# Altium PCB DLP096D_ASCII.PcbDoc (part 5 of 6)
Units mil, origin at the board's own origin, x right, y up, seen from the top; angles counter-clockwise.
Board outline 4950 x 3159.45 mil, 8 copper layers (Top Layer, GND1, SIGNAL1, POWER1, POWER2, SIGNAL2, GND2, Bottom Layer), stack 60.4 mil thick; 328 components, 223 nets, 1380 pads, 856 vias.

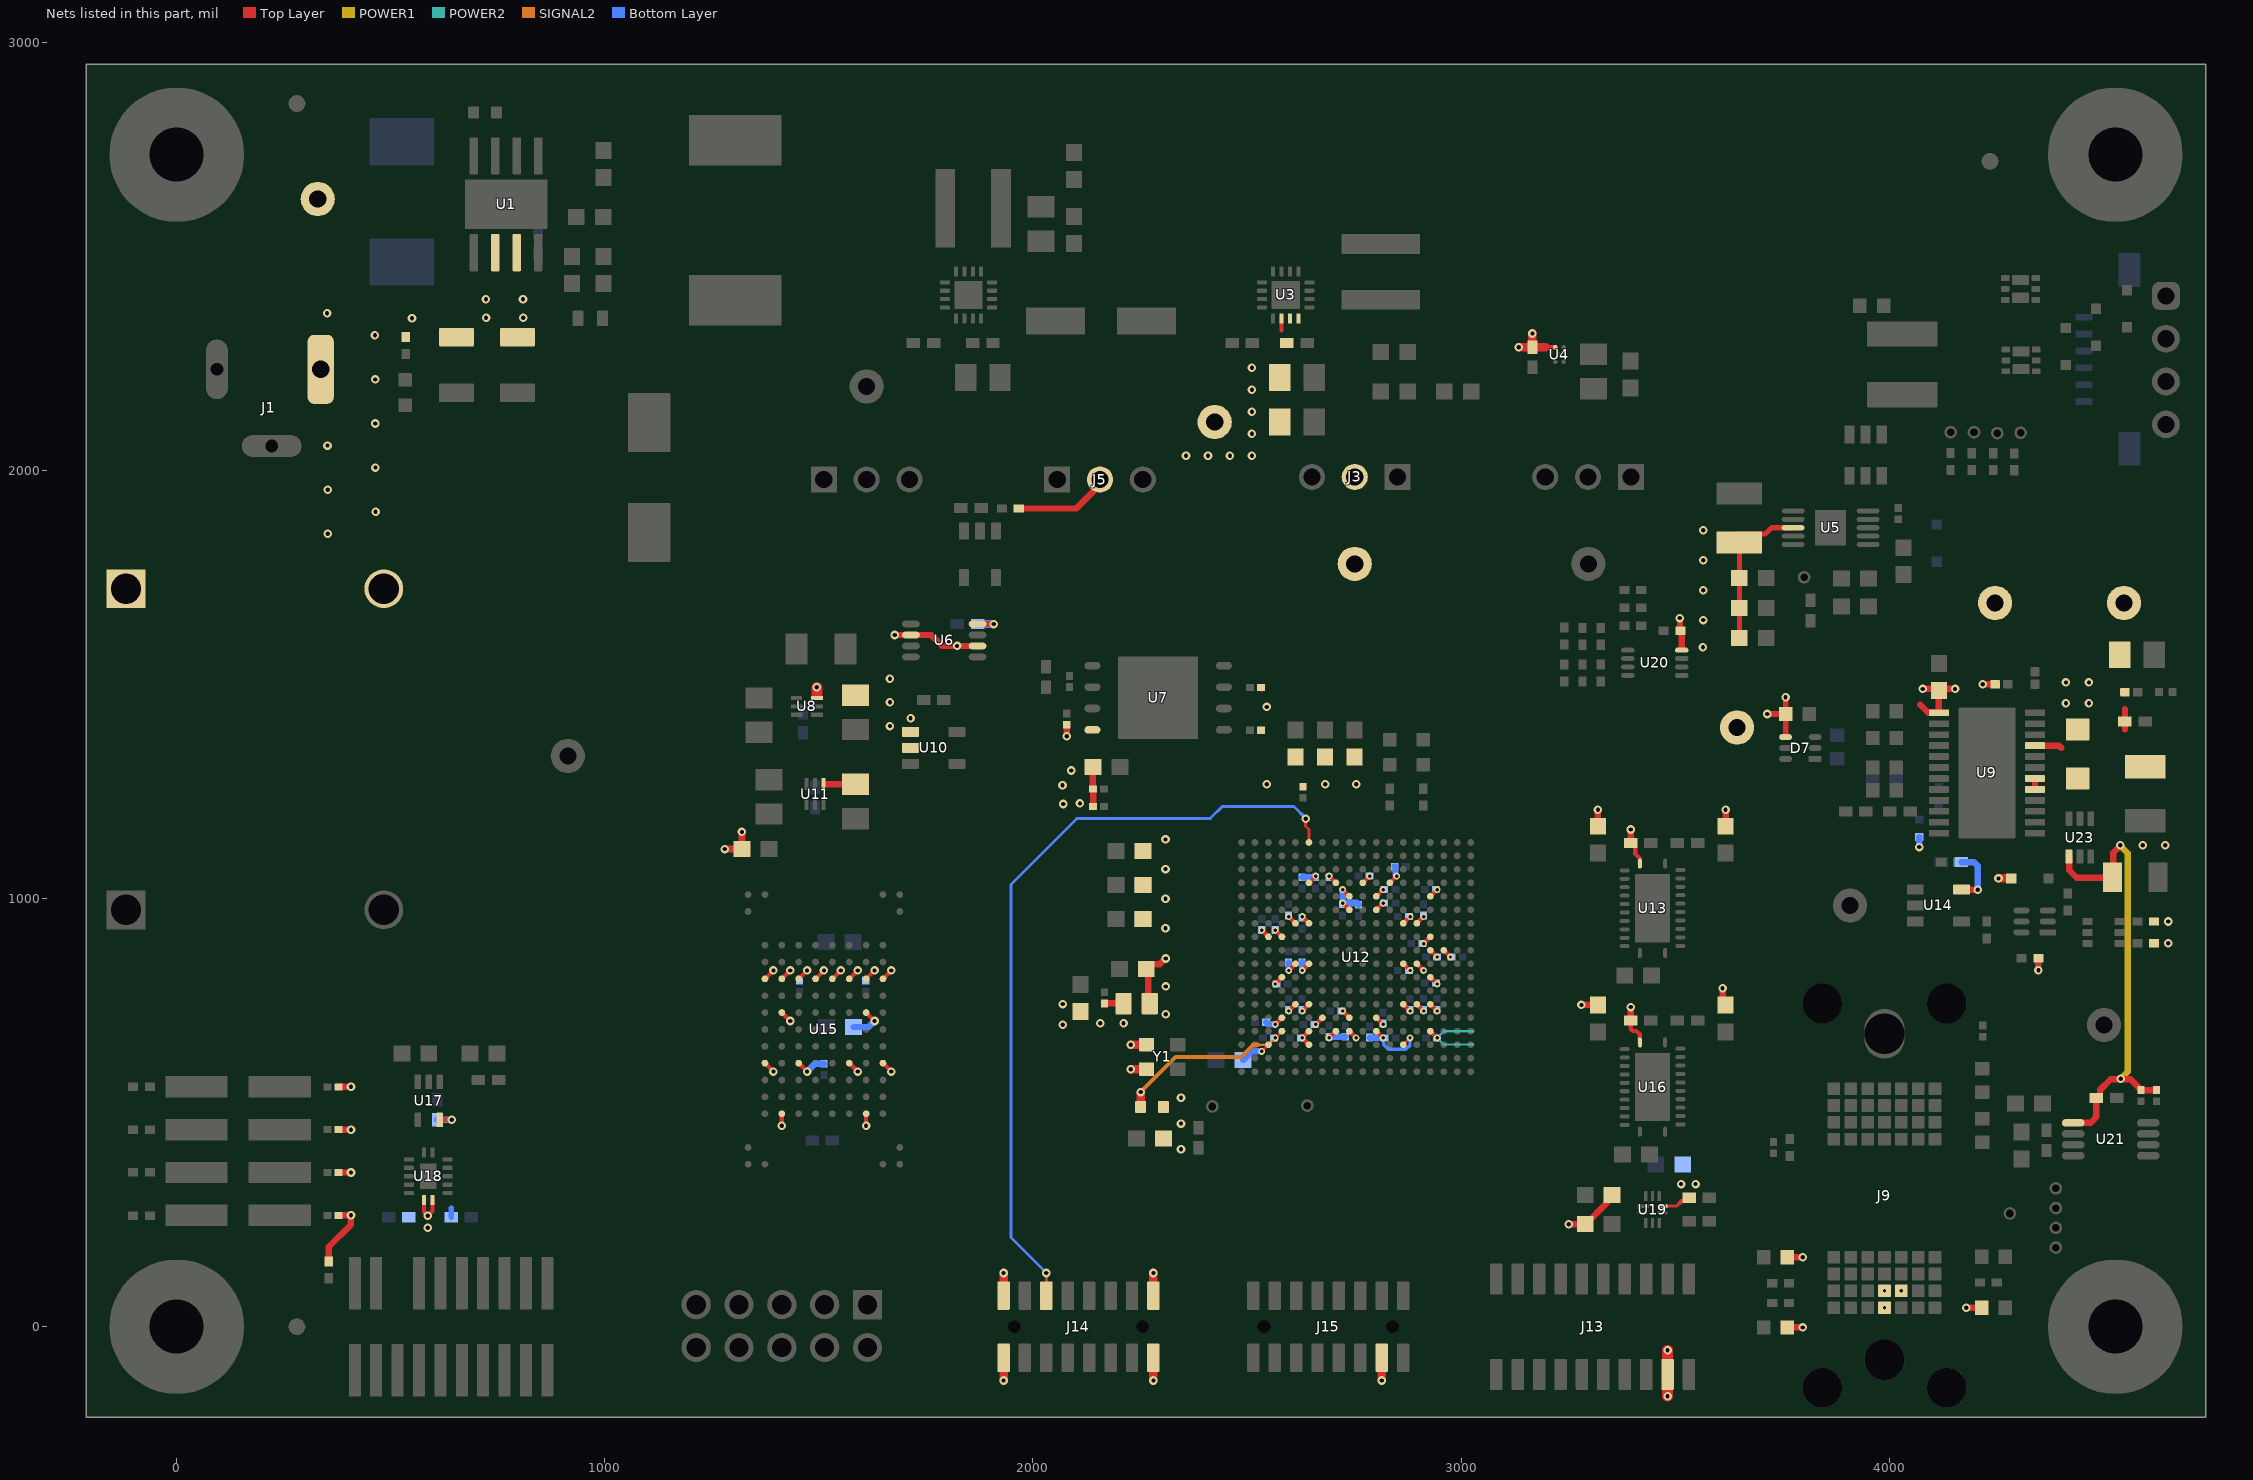
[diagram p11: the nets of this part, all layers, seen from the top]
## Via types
v1: diameter 20, hole 10, Top Layer to Bottom Layer, tented top, 596 vias
v2: diameter 16, hole 8, Top Layer to Bottom Layer, tented both sides, 126 vias
v3: diameter 16, hole 8.01, Top Layer to Bottom Layer, tented top, 63 vias
v4: diameter 19.68, hole 7.87, Top Layer to Bottom Layer, 37 vias
v5: diameter 16, hole 8.02, Top Layer to Bottom Layer, tented bottom, 22 vias
v6: diameter 24.8, hole 12.99, Top Layer to Bottom Layer, 6 vias
v7: diameter 19.68, hole 7.87, Top Layer to Bottom Layer, tented both sides, 6 vias

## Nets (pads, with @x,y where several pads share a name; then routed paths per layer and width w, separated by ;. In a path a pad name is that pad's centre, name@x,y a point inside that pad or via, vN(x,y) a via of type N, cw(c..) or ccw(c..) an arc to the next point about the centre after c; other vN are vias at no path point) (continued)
UART0_TXD: J14.12 U12.A6 | length 1831.9
  Top Layer w6.5: J14.12@2031.28,72.44 v1(2031.28,125.42) ; v1(2636.82,1186.35) 2636.82,1169.04 2644.56,1161.3 U12.A6@2644.56,1131.16
  Bottom Layer w6.5: v1(2031.28,125.42) 1948.36,208.34 1948.36,1033 2102.5,1187.14 2413.88,1187.14 2442,1215.25 2609.28,1215.25 2638.18,1186.35 v1(2636.82,1186.35)
VBIAS: C25.2 C64.1 J9.D15 R19.2 R42.2 TP8.1 U9.13 | length 275.3
  Top Layer w15: C64.1@3762.04,-1.74 v1(3797.78,-1.74) ; 4072.18,1452.7 4090.85,1434.04 U9.13@4115.92,1434.04 C25.2@4115.92,1489.65 ; v1(4078.14,1489.65) C25.2@4115.92,1489.65 ; v1(4153.71,1489.65) C25.2@4115.92,1489.65 ; v1(4218.45,1500.46) R19.2@4247.46,1500.46 ; v1(4348.41,832.48) R42.2@4348.41,860.32
  other v5: 3988.89,44.37
VDDA1V8_OSC_PLL_F: C553.1 FB2.2 U12.R4 | length 423.7
  Top Layer w6.5: v3(2565.82,674.47) U12.R4@2581.57,690.21
  Top Layer w20: FB2.2@2251.51,513.33 v1(2251.51,548.07)
  SIGNAL2 w5: 2525.52,658.67 2550.03,658.67 v3(2565.82,674.47)
  SIGNAL2 w10: v1(2251.51,548.07) 2333.18,629.75 2485.88,629.75 2514.8,658.67 2525.52,658.67
VDDA33_F: C46.1 C542.1 C543.1 C546.1 R74.2 U12.P7 U12.P9 U12.P11 | length 206.8
  Top Layer w10: v3(2660.31,705.96) U12.P7@2676.06,721.71 ; v3(2723.3,737.46) U12.P9@2739.05,721.71 ; U12.P11@2802.05,721.71 v3(2817.79,705.96)
  Top Layer w15: R74.2@2272.83,754.57 2268.76,758.63 2268.76,831.77 C46.1@2264.7,835.83 2275.9,847.03 2295.82,847.03 2308.73,859.94 v1(2310.09,859.94)
  other v1: 2310.09,729.65 2310.09,794.8
VDDA_LDO_1V8: C54.1 C547.1 C548.1 C549.1 C551.1 C552.1 FB2.1 U12.R6 U12.R8 U12.R11 U12.T6 U12.T13 | length 285.7
  Top Layer w6: U12.T13@2865.04,658.72 2865.04,658.89 2880.63,674.48 v3(2880.63,674.65)
  Top Layer w10: U12.T6@2644.56,658.72 v3(2628.82,674.47) U12.R6@2644.56,690.21 ; v3(2691.81,674.47) U12.R8@2707.56,690.21 ; U12.R11@2802.05,690.21 v3(2817.79,674.47)
  Bottom Layer w8: v3(2817.79,674.47) 2819.46,672.8 2819.46,658.05 2829.46,648.05 2871.08,648.05 2880.63,657.6 v3(2880.63,674.65)
  Bottom Layer w15: v3(2691.81,674.47) 2694.56,677.22 C547.1@2729.62,677.22 ; C549.1@2786.3,675.25 2817.01,675.25 v3(2817.79,674.47)
  other v1: 2345.8,414.17 2345.8,474.48 2345.8,534.79
VDDAR: C43.1 C44.1 C45.1 C509.1 C513.1 C515.1 C516.1 C517.1 C518.1 C519.1 C520.1 C521.1 C522.1 C523.1 C525.1 C528.1 C529.1 C530.1 C531.1 C532.1 C538.1 C539.1 C540.1 C541.1 J3.2 R36.2 TP6.1 U12.D10 U12.E9 U12.E11 U12.F9 U12.F11 U12.G5 U12.G6 U12.G13 U12.G14 U12.H3 U12.J15 U12.J16 U12.K5 U12.K6 U12.K13 U12.K14 U12.N5 U12.N6 U12.N13 U12.N14 U12.R9 | length 655.2
  Top Layer w10: v3(2534.33,926.43) U12.H3@2550.08,910.69 ; v3(2597.32,737.46) U12.N5@2613.07,753.21 ; v2(2597.32,831.95) U12.K5@2613.07,847.69 ; v3(2597.32,957.93) U12.G5@2613.07,942.18 ; v3(2628.82,737.46) U12.N6@2644.56,753.21 ; v2(2628.82,831.95) U12.K6@2644.56,847.69 ; v3(2628.82,957.93) U12.G6@2644.56,942.18 ; v3(2723.3,989.43) U12.F9@2739.05,973.68 ; v2(2723.3,1020.92) U12.E9@2739.05,1005.17 ; U12.R9@2739.05,690.21 v2(2754.8,674.47) ; U12.D10@2770.55,1036.67 v3(2786.3,1052.42) ; U12.F11@2802.05,973.68 v3(2817.79,989.43) ; U12.E11@2802.05,1005.17 v3(2817.79,1020.92) ; U12.N13@2865.04,753.21 v3(2880.79,737.46) ; U12.K13@2865.04,847.69 v3(2880.79,831.95) ; U12.G13@2865.04,942.18 v3(2880.79,957.93) ; U12.N14@2896.53,753.21 v3(2912.28,737.46) ; U12.K14@2896.53,847.69 v2(2912.28,831.95) ; U12.G14@2896.53,942.18 v3(2912.28,957.93) ; U12.J15@2928.03,879.19 v3(2943.78,863.44) ; U12.J16@2959.53,879.19 v3(2975.27,863.44)
  Top Layer w15.75: v1(1280.27,1115.55) R36.2@1320.27,1115.55 v1(1320.27,1155.55)
  Bottom Layer w15.75: C529.1@2597.27,850.28 2597.27,831.99 v2(2597.32,831.95) ; v2(2628.82,831.95) C528.1@2628.82,850.45 ; v2(2723.3,1020.92) v3(2723.3,989.43) 2756.47,989.43 2759.2,986.7 2759.99,986.7 2760.38,986.3 C520.1@2760.38,985.51
  other v1: 2309.5,930.36 2309.5,999.59 2309.5,1068.81 2309.5,1138.04
VDDS33: C9.1 C10.1 C13.1 C30.1 C31.1 C32.1 C35.1 C36.1 C38.1 C39.2 C41.1 C47.1 C48.1 C49.1 C56.1 C65.1 C71.1 C501.1 C507.1 C508.1 C510.1 C524.1 C527.1 C533.1 C534.1 C535.1 C544.1 C545.1 C550.1 C555.1 C556.1 C557.2 J5.2 J13.3 J14.1 J14.2 J14.15 J14.16 J15.3 R10.2 R23.2 R25.2 R26.2 R29.2 R34.1 R35.1 R44.1 R45.1 R47.2 R63.2 R67.2 R69.2 R70.2 R72.1 R74.1 R75.1 R77.2 R85.2 R86.2 R505.2 R532.1 TP5.1 U3.10 U3.11 U3.12 U4.A1 U6.8 U7.8 U12.D8 U12.D12 U12.H4 U12.H15 U12.L15 U12.P4 U12.R15 U13.1 U14.5 U15.F2 U15.F3 U15.F4 U15.F5 U15.F6 U15.F7 U15.F8 U15.F9 U15.H3 U15.H8 U15.L2 U15.L4 U15.L7 U15.L9 U15.P3 U15.P8 U16.1 U17.5 U18.1 U18.14 U19.7 U20.8 U21.1 U23.1 | length 4153.9
  Top Layer w7: U19.7@3470.73,281.42 3503.17,281.42 3509.54,287.79
  Top Layer w9.4: 2580.55,2326.58 U3.10@2580.55,2354.73
  Top Layer w9.8: U18.14@577.74,296.29 577.74,268.23 v1(586.67,259.31) 597.43,270.06 U18.1@597.43,296.29 ; U17.5@614.46,483.25 v1(642.38,483.25)
  Top Layer w10: U15.L2@1374.03,615.56 v1(1393.72,595.88) ; U15.F2@1374.03,812.41 v1(1393.72,832.1) ; v1(1413.4,469.61) U15.P3@1413.4,497.45 ; U15.H3@1413.4,733.67 v1(1433.09,713.99) ; U15.F3@1413.4,812.41 v1(1433.09,832.1) ; U15.L4@1452.77,615.56 v1(1472.46,595.88) ; U15.F4@1452.77,812.41 v1(1472.46,832.1) ; U15.F5@1492.14,812.41 v1(1511.83,832.1) ; U15.F6@1531.51,812.41 v1(1551.2,832.1) ; U15.L7@1570.88,615.56 v1(1590.57,595.88) ; U15.F7@1570.88,812.41 v1(1590.57,832.1) ; v1(1610.25,469.61) U15.P8@1610.25,497.45 ; U15.H8@1610.25,733.67 v1(1629.94,713.99) ; U15.F8@1610.25,812.41 v1(1629.94,832.1) ; U15.L9@1649.62,615.56 v1(1669.31,595.88) ; U15.F9@1649.62,812.41 v1(1669.31,832.1) ; v2(2565.82,705.96) U12.P4@2581.57,721.71 ; v3(2565.82,926.43) U12.H4@2581.57,910.69 ; v3(2691.81,1052.42) U12.D8@2707.56,1036.67 ; U12.D12@2833.54,1036.67 v3(2849.29,1052.42) ; v3(2912.28,894.94) U12.H15@2928.03,910.69 ; U12.R15@2928.03,690.21 v3(2943.78,674.47) ; U12.L15@2928.03,816.2 v3(2943.78,800.45) ; 3197.67,2287.86 U4.A1@3219.56,2287.86 ; C49.1@3396.24,714.84 3396.24,695.62 3400.96,690.9 3409.55,690.9 3417.54,682.9 U16.1@3417.54,664.13 ; C41.1@3396.24,1129.49 3400.13,1129.49 3406.94,1122.68 3406.94,1104.36 3417.54,1093.75 U13.1@3417.54,1081.62 ; 3509.54,287.79 3516.22,294.47 3525.48,294.47 C56.1@3532.29,301.28
  Top Layer w14.5: U6.8@1870.52,1641.21 v1(1908.39,1641.21) ; v1(2078.92,1378.88) R25.2@2078.92,1405.98
  Top Layer w15: R75.1@355.48,152.65 355.48,186.96 406.22,237.7 406.22,259.24 v1(407.18,260.2) R70.2@378.12,260.2 ; R67.2@378.12,360.2 v1(407.18,360.2) ; R63.2@378.12,460.2 v1(407.18,460.2) ; R47.2@378.12,560.2 v1(407.18,560.2) ; R77.2@1966.86,1911 2101.29,1911 2156.54,1966.24 J5.2@2156.54,1978.66 ; C35.1@2140.07,1256.14 C38.1@2140.07,1307.14 ; C36.1@2140.66,1216.46 C35.1@2140.66,1256.14 ; C48.1@2167.41,755.02 2211.29,755.02 R74.1@2211.74,754.57 ; R23.2@2532.81,1493.21 2533.6,1493.21 2534.37,1492.44 R23.2@2534.37,1491.65 ; R29.2@2631.07,1261.37 R29.2@2631.07,1262.16 ; C31.1@2682.04,1330.49 C31.1@2682.46,1330.07 ; C32.1@2751.51,1330.49 C32.1@2754.33,1327.67 ; v1(3251.14,239.44) R72.1@3289.83,239.44 3290.81,239.44 3340.63,289.26 3340.63,296.71 3351.84,307.91 R69.2@3352.82,307.91 ; v1(3280.94,751.51) R44.1@3319.63,751.51 ; R34.1@3319.63,1169 v1(3319.63,1207.69) ; C49.1@3396.24,714.84 v1(3396.24,746.65) ; C41.1@3396.24,1129.49 v1(3396.24,1161.3) ; v1(3510.51,1655.12) 3511.32,1654.32 3511.32,1626 C65.1@3512.12,1625.2 3513.07,1625.2 3515.42,1622.86 U20.8@3515.5,1583.57 ; v1(3610.77,790.2) 3610.77,758.51 R45.1@3617.77,751.51 ; R35.1@3617.77,1169 v1(3617.77,1207.69) ; U14.5@4170.76,1020.81 v1(4206.6,1020.81) ; U23.1@4419.7,1098.19 4420.07,1097.82 4420.07,1066.17 4437.83,1048.42 4520.04,1048.42 C39.2@4521.41,1049.8 4523.25,1051.64 4523.25,1106.75 4539.82,1123.31 v1(4539.82,1124.66) ; U21.1@4429.64,476.05 4430.16,476.57 4470.41,476.57 4483.88,490.04 C71.1@4483.92,533.99 ; C71.1@4483.92,533.99 4487.86,533.99 4492.17,538.31 4492.17,553 4517.29,578.13 4563.5,578.13 4588.16,553.47 R86.2@4588.16,552.68 R86.2@4588.16,552.68 4624.57,552.74 R85.2@4624.63,552.8
  Top Layer w20: v1(1931.28,-125.61) J14.15@1931.28,-72.63 ; J14.16@1931.28,72.44 v1(1931.28,125.42) ; v1(2281.28,-125.61) J14.1@2281.28,-72.63 ; J14.2@2281.28,72.44 v1(2281.28,125.42) ; v1(2814.59,-125.61) J15.3@2814.59,-72.63 ; v1(3134.61,2287.78) C10.1@3166.6,2287.78 ; C10.1@3166.54,2287.84 v1(3166.54,2319.83) ; C10.1@3166.66,2287.84 3197.65,2287.84
  Top Layer w25: v1(3482.19,-162.54) J13.3@3482.19,-111.32 v1(3482.19,-55.1)
  POWER1 w15: v1(4539.82,1124.66) 4539.82,1123.31 4557.06,1106.06 4557.06,595.82 v1(4540.62,579.38)
  POWER2 w5: 3028.53,658.84 2959.4,658.84 v3(2943.78,674.47) 2959.4,690.09 3028.53,690.09
  Bottom Layer w13: C557.2@640.94,255.67 640.94,276.36
  Bottom Layer w14.5: C544.1@1580.81,699.84 1615.79,699.84 v1(1629.94,713.99)
  Bottom Layer w15: C555.1@608.54,483.25 v1(642.38,483.25) ; v1(1472.46,595.88) 1490.74,614.16 R505.2@1511.83,614.16 ; C545.1@2544.54,711.16 2549.74,705.96 v2(2565.82,705.96) ; C508.1@2845.15,1074.92 2845.93,1074.92 2846.7,1074.15 2846.7,1055.28 2849.29,1052.69 v3(2849.29,1052.42) ; C507.1@4168.68,1085.17 4197.93,1085.17 4206.6,1076.5 v1(4206.6,1020.81)
  Bottom Layer w18: C501.1@1870.52,1641.21 v1(1908.39,1641.21)
  other v1: 586.67,230.81 3513.67,333.1 3547.64,333.1 2069.43,704.98 2157.29,709.06 2211.55,709.06 2069.43,753.61 4592.26,1124.66 4644.7,1124.66 2070.88,1220.9 2109.59,1222.24 2069.02,1264.82 2546.15,1267.13 2682.88,1267.13 2755.29,1267.13 2089.29,1299.09 2546.15,1447.52 2357.43,2034.54 2408.75,2034.54 2460.07,2034.54 2511.39,2034.54 2511.39,2085.86 2511.39,2137.18 2511.39,2188.5 2511.39,2239.82
VDDS_LDO_1V8: C511.1 C512.1 C514.1 C536.1 C537.1 C554.1 U12.D6 U12.E15 U12.L4 U12.N15 U12.T3 Y1.1 Y1.4 | length 268.1
  Top Layer w6.5: v2(2534.33,642.97) U12.T3@2550.08,658.72
  Top Layer w10: v3(2565.82,800.45) U12.L4@2581.57,816.2 ; U12.D6@2644.56,1036.67 v3(2660.31,1052.42) ; U12.N15@2928.03,753.21 v3(2943.78,737.46) ; U12.E15@2928.03,1005.17 v3(2943.78,1020.92)
  Top Layer w20: v1(2228.69,601.63) Y1.1@2265.4,601.63 ; v1(2228.69,658.72) Y1.4@2265.4,658.72
  Bottom Layer w15: C554.1@2490.84,622.93 2510.87,642.97 v2(2534.33,642.97) ; C512.1@2628.82,1049.66 C511.1@2660.31,1049.66
VIN_12V: C4.2 C5.2 C19.1 C22.1 C23.1 J1.1 J7.1 J7.2 R4.2 R11.2 TP1.1 U1.2 U1.3 U5.8 | length 363.5
  Top Layer w11.81: R11.2@3641.71,1851.01 3709.78,1851.01 3724.88,1866.11 U5.8@3775.35,1866.11 ; C23.1@3649.76,1608.27 C22.1@3649.76,1678.72 C19.1@3649.76,1749.17 R11.2@3649.76,1831.85
  other v1: 3564.73,1587.21 3565.53,1650.48 3565.53,1720.35 3565.53,1790.22 353.04,1852.14 3565.53,1860.1 464.56,1903.62 352.68,1955.1 464.2,2006.58 352.32,2058.06 463.83,2109.54 463.47,2212.5 463.11,2315.46 549.63,2355.6 722.66,2356.32 809.18,2356.69 351.23,2366.94 722.3,2399.51 808.82,2399.87
VMON_1V2: R28.1 U10.2 U11.4 | length 72.6
  Top Layer w15: U11.4@1513.19,1266.64 R28.1@1585.77,1266.64
VMON_5V: R22.1 U6.2 U6.6 U8.6 U10.1 | length 221.5
  Top Layer w14.5: v1(1677.13,1615.62) 1762.51,1615.62 1788.1,1590.03 1832.64,1590.03 U6.6@1870.52,1590.03
  Top Layer w25: 1495.69,1476.26 v1@1495.69,1493.74
  other v1: 1665.91,1402.93 1714.05,1421.28 1665.91,1458.25 1494.69,1493.81 1665.91,1513.58 1822.64,1590.03
VOFFSET: C24.1 C29.1 C63.1 D4.1 D8.1 J9.E14 R20.2 TP9.1 U9.9 | length 177.2
  Top Layer w15: v1(4179.99,44.37) C63.1@4215.74,44.37 ; U9.9@4340.33,1357.27 4396.7,1357.27 4402.24,1351.73 ; 4550.61,1395.22 C29.1@4550.61,1413.83 4550.61,1442.67
  Top Layer w20: v1(4255.18,1046.98) D8.1@4284.99,1046.98
  other v1: 4412.61,1456.36 4466.43,1456.36 4412.61,1504.75 4466.43,1504.75
  other v5: 4028.26,83.74
VOFFSET_SW: D4.2 L6.2 U9.5 U9.6 | length 25.6
  Top Layer w15: U9.5@4340.33,1254.9 U9.6@4340.33,1280.49
VRESET: C28.1 C59.1 D7.4 J9.D14 R40.1 R41.1 R504.2 TP10.1 | length 195.2
  Top Layer w13: v1(3714.79,1431.09) C28.1@3757.81,1431.09 ; D7.4@3757.81,1377.2 C28.1@3757.81,1431.09 ; v1(3757.81,1469.96) C28.1@3757.81,1431.09
  Top Layer w15: C59.1@3762.04,162.48 v1(3797.78,162.48)
  Bottom Layer w15: v1(4069.89,1120.18) R504.2@4069.89,1143.83
  other v1: 4651.59,895.3 4651.59,946.48
  other v5: 3988.89,83.74
pads on no net: FID1.1 FID2.1 FID3.1 FID4.1 FID5.1 FID6.1 H500.0 H501.0 H502.0 H503.0 J9. J9.A12 J9.D3 J9.D4 J9.D5 J9.E2 J9.F5 J9.G5 J11.1 J11.3 J11.4 J11.6 J12.2 J12.9 J12.13 J12.14 J12.15 J12.17 J12.18 J12.19 J14. J15. J15.14 LBL1.0 U1.6 U2.17@1849.56,2409.85 U3.17@2590.39,2409.85 U8.5 U9.2 U9.3 U9.10 U9.25@4228.13,1293.29 U11.3 U12.A9 U12.B1 U12.B7 U12.B9 U12.B10 U12.B16 U12.C1 U12.C3 U12.C7 U12.C12 U12.C13 U12.C14 U12.D2 U12.D4 U12.D11 U12.D14 U12.D15 U12.E1 U12.E3 U12.E4 U12.F1 U12.F2 U12.F3 U12.F4 U12.F17 U12.G1 U12.G2 U12.G3 U12.G4 U12.G17 U12.H1 U12.H2 U12.H16 U12.H17 U12.H18 U12.J2 U12.J3 U12.J17 U12.J18 U12.K15 U12.K16 U12.K17 U12.K18 U12.L16 U12.L17 U12.L18 U12.M15 U12.M16 U12.N3 U12.N17 U12.N18 U12.P2 U12.R1 U12.R3 U12.R7 U12.R10 U12.R12 U12.R14 U12.T7 U12.T8 U12.T9 U12.T10 U12.T11 U12.T12 U12.T14 U12.T15 U12.T18 U12.U3 U12.U4 U12.U5 U12.U6 U12.U7 U12.U8 U12.U9 U12.U10 U12.U11 U12.U12 U12.U13 U12.U14 U12.U15 U12.U16 U12.U18 U12.V2 U12.V3 U12.V4 U12.V5 U12.V6 U12.V7 U12.V8 U12.V9 U12.V10 U12.V11 U12.V12 U12.V13 U12.V14 U12.V15 U14.1 U15.A1 U15.A2 U15.A9 U15.A10 U15.B1 U15.B10 U15.D2 U15.D3 U15.D4 U15.D5 U15.D6 U15.D7 U15.D8 U15.D9 U15.E2 U15.E3 U15.E5 U15.E6 U15.E7 U15.E8 U15.E9 U15.H4 U15.H5 U15.H6 U15.H7 U15.J2 U15.J3 U15.J4 U15.J6 U15.J7 U15.J8 U15.J9 U15.K4 U15.K5 U15.K6 U15.K7 U15.K8 U15.K9 U15.L5 U15.L6 U15.M2 U15.M3 U15.M6 U15.M8 U15.M9 U15.N4 U15.N5 U15.N6 U15.N7 U15.N8 U15.N9 U15.P4 U15.P7 U15.T1 U15.T10 U15.U1 U15.U2 U15.U9 U15.U10 U17.1 U18.6 U18.9 U21.4 U21.6 U22.4 U22.5 U23.4 U23.5

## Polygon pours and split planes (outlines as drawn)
NetL6_1 on Top Layer "GND" (solid, remove dead copper, pour order 1283): 4392.21,1154.62 4355.37,1236.84 4674.78,1236.84 4674.78,1154.62
VOFFSET on Top Layer "TOP_LAYER_VOFFSET_P1297" (solid, remove dead copper, pour order 1297): 4508.17,1342.13 4543.71,1377.67 4558.21,1377.67 4565.36,1384.82 4565.36,1606.12 4611.62,1652.38 4611.62,1743.06 4595.71,1758.97 4392.22,1758.97 4377.95,1744.7 4377.95,1347.62 4383.44,1342.13
VBIAS on Top Layer "GND" (solid, remove dead copper, pour order 1253): 4168.2,1494.75 4154.35,1508.59 4076.26,1508.59 4064.88,1497.21 4064.88,1448.3 4091.64,1421.54 4160,1421.54 4160,1452.72 4168.2,1460.91
5V on Top Layer "TOP_LAYER_5V_P1299" (solid, remove dead copper, pour order 1299): 1898.94,1911.84 1898.94,2371.63 1834.25,2371.63 1830.84,2368.23 1830.84,2328.09 1773.59,2270.84 1545.87,2270.84 1522.3,2247.27 1522.3,2121.63 1570.37,2073.56 1570.37,1940.78 1599.31,1911.84
3V3_OB on Top Layer "TOP_LAYER_3V3_OB_P1294" (solid, remove dead copper, pour order 1294): 1899.05,2620.99 2049.63,2620.99 2144.25,2526.38 2144.25,2112.19 2091.48,2059.42 2091.48,1915.58 2081.65,1905.75 1995.36,1905.75 1985.56,1915.55 1985.56,2305.48 1943.5,2347.55 1943.5,2363.28 1899.05,2407.73
LED_ANODE on Top Layer "TOP_LAYER_LED_ANODE_P1342" (solid, remove dead copper, pour order 1342): 4013.7,2284.84 4110.59,2284.84 4129.47,2303.72 4129.47,2382.15 4222.26,2474.94 4274.34,2474.94 4290.29,2458.99 4290.29,2444.48 4297.44,2437.33 4380.42,2437.33 4393.16,2424.59 4393.16,2323.94 4402.04,2315.06 4429.56,2315.06 4473.61,2359.11 4673.81,2359.11 4701.84,2387.13 4701.84,2435.18 4592.26,2544.76 4093.38,2544.76 3968.3,2419.68 3968.3,2330.24
GND on Top Layer "TOP_LAYER_GND_P1341" (solid, remove dead copper, pour order 1341): 2258.03,2418.22 2342.56,2418.22 2374.16,2386.61 2374.16,2318.16 2338.06,2282.06 2258.03,2282.06
VRESET on Top Layer "TOP_LAYER_VRESET_P1246" (solid, remove dead copper, pour order 1246): 4657.26,866.92 4609.75,866.92 4606.22,870.45 4606.22,974.92 4609.42,978.12 4656.77,978.12 4663.88,971.02 4663.88,873.54
VIN_12V on Top Layer "TOP_LAYER_VIN_12V_P1287" (solid, remove dead copper, pour order 1287): 3728.77,1873.47 3728.77,1822.05 3708.87,1802.15 3694.06,1802.15 3672.8,1780.89 3672.8,1565.32 3661.61,1554.13 3551.24,1554.13 3543.42,1561.95 3543.42,1877.3 3552.1,1885.97 3716.27,1885.97
VIN_12V on Top Layer "TOP_LAYER_VIN_12V_P1304" (solid, remove dead copper, pour order 1304): -157.93,1579 544.95,1579 592,1626.05 592,1886.85 486.84,1992.02 486.84,2262.62 515.04,2290.81 561.45,2290.81 597.12,2255.15 611,2255.15 849.5,2255.15 860.19,2265.84 860.19,2394.8 823.53,2431.46 823.53,2526.28 818.71,2531.1 722.93,2531.1 716.81,2524.97 716.8,2446.16 698.82,2428.18 564.16,2428.18 539.46,2452.87 539.46,2674.65 514.43,2699.69 205.61,2699.69 71.21,2565.28 -161.38,2565.28 -202.14,2524.52 -202.14,1623.21
VOFFSET_SW on Top Layer "TOP_LAYER_VOFFSET_SW_P1284" (solid, remove dead copper, pour order 1284): 4664.5,1362.4 4549.76,1362.4 4520.1,1332.74 4405.36,1332.74 4360.7,1288.07 4320.85,1288.07 4314.79,1282.02 4314.79,1246.93 4665.02,1246.93 4674.65,1256.56 4674.65,1352.25
1V2_OB on Top Layer "TOP_LAYER_1V2_OB_P1296" (solid, remove dead copper, pour order 1296): 2867.71,2338.71 2926.68,2338.71 2935.13,2347.16 2935.13,2439.33 2928.93,2445.53 2707.09,2445.53 2667.21,2405.66 2667.21,2395.32 2684.37,2378.16 2684.37,2344.03 2739.98,2288.42 2739.98,2071.1 2796.27,2014.81 2796.27,1944.06 2810,1930.33 2907.76,1930.33 2917.43,1940.01 2917.43,2073.04 2837.46,2153.01 2837.46,2308.46
VDDS33 on Top Layer "TOP_LAYER_VDDS33_P1279" (solid, remove dead copper, pour order 1279): 2159.92,1239.63 2167.9,1247.61 2167.9,1406.36 2158.46,1415.8 2062.3,1415.8 2057.7,1411.2 2057.7,1179.76 2064.12,1173.34 2151.2,1173.34 2160.11,1182.24 2160.11,1230.3
VMON_5V on Top Layer "TOP_LAYER_VMON_5V_P1278" (solid, pour order 1278): 1749.14,1377.32 1655.23,1377.32 1644.79,1387.77 1644.79,1437.47 1633.18,1449.07 1553.49,1449.07 1539.26,1463.3 1478.61,1463.3 1474.89,1467.03 1474.89,1519.04 1483.7,1527.86 1694.55,1527.86 1718.94,1503.47 1718.94,1455.85 1755.05,1419.74 1755.05,1383.23
5V on Top Layer "TOP_LAYER_5V_P1286" (solid, remove dead copper, pour order 1286): 1417.88,1317.49 1305.19,1317.49 1297.42,1325.26 1297.42,1426.71 1304.05,1433.34 1400.11,1433.34 1409.36,1424.09 1421.26,1424.09 1435.49,1438.32 1630.24,1438.32 1634.44,1434.12 1634.44,1352.09 1627.73,1345.39 1513.8,1345.39 1476.12,1307.71 1476.1,1253.5 1433.27,1253.5 1429.68,1257.09 1429.68,1305.68
5V on Top Layer "TOP_LAYER_5V_P1255" (solid, remove dead copper, pour order 1255): 1775.93,1490.64 1775.93,1383.7 1783.52,1376.11 1856.1,1376.11 1861.67,1381.68 1861.67,1488.81 1854.61,1495.86 1781.15,1495.86
LED_ANODE on Top Layer "TOP_LAYER_LED_ANODE_P1261" (solid, remove dead copper, pour order 1261): 3843.5,1794.9 3843.5,1635.79 3852.83,1626.46 3908.13,1626.46 3915.73,1634.06 3915.73,1796.39 3909.32,1802.8 3851.4,1802.8
GND on Top Layer "TOP_LAYER_GND_P1271" (solid, pour order 1271): 2793.95,1376.51 2793.95,1436.18 2784.15,1445.98 2586.04,1445.98 2576.97,1436.91 2576.97,1378.61 2585.86,1369.71 2787.14,1369.71
VDDS33 on Top Layer "TOP_LAYER_VDDS33_P1285" (solid, pour order 1285): 2780.4,1252.34 2537.33,1252.34 2523.57,1266.1 2523.57,1517.97 2531.55,1525.95 2559.09,1525.95 2566.81,1518.22 2566.81,1369.52 2583.94,1352.39 2782.25,1352.39 2792.41,1342.24 2792.41,1264.35
GND on Top Layer "TOP_LAYER_GND_P1273" (solid, remove dead copper, pour order 1273): 3647.32,-32.87 3654.09,-39.63 3722.16,-39.63 3727.23,-34.56 3727.23,19.8 3739.91,32.48 3739.91,79.51 3739.91,131.01 3724.05,146.86 3724.05,195.94 3719.29,200.71 3654.81,200.71 3647.14,193.04
DMD_1V8 on Top Layer "TOP_LAYER_DMD_1V8_P1248" (solid, remove dead copper, pour order 1248): 3752.67,32.48 3752.67,126.53 3758.36,132.22 3810.01,132.22 3815.82,126.42 3815.82,31.81 3809.71,25.7 3759.45,25.7
NetC17_2 on Top Layer "TOP_LAYER_NETC17_2_P1295" (solid, remove dead copper, pour order 1295): 4138.31,2230.07 3924.96,2230.07 3915.31,2220.42 3915.31,2144.42 3936.85,2122.88 3936.85,1949.03 3921.95,1934.13 3921.95,1903.03 3927.35,1897.63 4135.87,1897.63 4151.96,1913.72 4151.96,2216.42
GND on Top Layer "TOP_LAYER_GND_P1259" (solid, remove dead copper, pour order 1259): 3860.25,1954.43 3865.29,1949.39 3915.1,1949.39 3926.24,1960.53 3926.25,2112.17 3914.3,2124.11 3867.06,2124.11 3860.25,2117.31
VRESET on Top Layer "TOP_LAYER_VRESET_P1280" (solid, remove dead copper, pour order 1280): 3576.1,1367.68 3565.68,1378.09 3565.68,1481.94 3575.74,1492 3770.6,1492 3782.57,1480.03 3782.57,1376.2 3774.04,1367.68
GND on Top Layer "TOP_LAYER_GND_P1249" (solid, remove dead copper, pour order 1249): 4336.9,884.06 4340.79,880.16 4476.52,880.16 4480.37,884.02 4480.37,929.03 4476.12,933.29 4341.18,933.29 4336.9,929.01
GND on Top Layer "TOP_LAYER_GND_P1277" (solid, remove dead copper, pour order 1277): 3784.41,1554.33 3703.45,1554.33 3693.41,1564.37 3693.41,1772.67 3705.68,1784.94 3789.75,1784.94 3799.01,1775.68 3799.01,1568.93
VDDA_LDO_1V8 on Top Layer "TOP_LAYER_VDDA_LDO_1V8_P1260" (solid, remove dead copper, pour order 1260): 2292.88,551.03 2350.84,551.03 2359.81,542.06 2359.81,406.88 2348.84,395.91 2287.27,395.91 2281.38,401.8 2281.38,539.53
GND on Top Layer "TOP_LAYER_GND_P1275" (solid, remove dead copper, pour order 1275): 2133.35,1157.19 2204.82,1157.19 2214.09,1147.7 2214.09,925.39 2200.02,911.33 2134.91,911.33 2122.21,924.02 2122.21,1146.06
VDDAR on Top Layer "TOP_LAYER_VDDAR_P1274" (solid, remove dead copper, pour order 1274): 2317.54,1157.19 2246.07,1157.19 2236.8,1147.7 2236.8,925.39 2250.86,911.33 2315.98,911.33 2328.67,924.02 2328.67,1146.06
GND on Top Layer "TOP_LAYER_GND_P1269" (solid, remove dead copper, pour order 1269): 2078.82,772.08 2065.89,785.01 2065.89,862.95 2073.74,870.8 2219.92,870.8 2224.98,865.74 2224.98,777.53 2219.53,772.08
VDDS33 on Top Layer "TOP_LAYER_VDDS33_P1264" (solid, remove dead copper, pour order 1264): 2222.76,766.43 2062.85,766.43 2058.08,761.66 2058.08,689.9 2063.75,684.23 2224.95,684.23 2231.25,690.53 2231.25,757.94
VDDA33_F on Top Layer "TOP_LAYER_VDDA33_F_P1262" (solid, remove dead copper, pour order 1262): 2325.79,722.07 2325.79,870.28 2317.51,878.56 2251.5,878.56 2244.84,871.9 2244.84,721.34 2252.16,714.01 2317.74,714.01
5V on Top Layer "TOP_LAYER_5V_P1263" (solid, remove dead copper, pour order 1263): 1496.19,1233.56 1495.42,1234.33 1486.21,1234.33 1482.94,1231.07 1482.94,1131.23 1491.3,1122.88 1636.09,1122.88 1642.91,1129.7 1642.91,1207.01 1636.36,1213.56 1537.43,1213.55 1520.38,1196.51 1501.34,1196.51 1496.19,1201.67
VMON_1V2 on Top Layer "TOP_LAYER_VMON_1V2_P1276" (solid, remove dead copper, pour order 1276): 1530.24,1221.77 1525.17,1226.83 1525.17,1233.28 1512.41,1246.04 1509.05,1246.04 1505.36,1249.74 1505.36,1322.47 1516.54,1333.66 1632.47,1333.66 1644.79,1345.97 1644.79,1371.8 1649.19,1376.2 1738.26,1376.2 1742.34,1372.13 1742.34,1339.76 1736.23,1333.66 1688.05,1333.65 1675.83,1321.44 1675.83,1229.43 1668.17,1221.77
GND on Top Layer "TOP_LAYER_GND_P1267" (solid, remove dead copper, pour order 1267): 547.75,671.91 538.39,681.27 467.75,681.27 462.45,675.97 462.45,534.03 468.04,528.43 569.7,528.43 575.86,534.6 575.86,588.4 547.75,616.51
NetL3_1 on Top Layer "TOP_LAYER_NETL3_1_P1290" (solid, remove dead copper, pour order 1290): 2646.4,2449.62 2661.28,2464.5 2925.47,2464.5 2935.13,2473.79 2935.13,2591.72 2923.29,2603.56 2586.25,2603.56 2569.95,2587.26 2569.95,2454.83 2575.16,2449.62
DMD_1V8_OB on Top Layer "TOP_LAYER_DMD_1V8_OB_P1293" (solid, remove dead copper, pour order 1293): 3234.66,2217.47 3234.66,1940.34 3247.96,1927.04 3459.33,1927.04 3471.83,1939.54 3471.83,2211.98 3450.05,2233.77 3250.96,2233.77
GND on Top Layer "TOP_LAYER_GND_P1254" (solid, remove dead copper, pour order 1254): 2851.21,2301.16 2873.49,2323.43 2936.76,2323.44 2944.78,2315.41 2944.78,2229.99 2939.64,2224.84 2860.56,2224.84 2851.21,2234.19
GND on Top Layer "TOP_LAYER_GND_P1266" (solid, remove dead copper, pour order 1266): 2714.44,2164.92 2724.79,2175.27 2724.79,2282.43 2691.03,2316.19 2623.86,2316.19 2621.06,2313.39 2621.06,2180.97 2637.11,2164.92
VDDS33 on Top Layer "TOP_LAYER_VDDS33_P1300" (solid, remove dead copper, pour order 1300): 2232.23,2063.79 2119.64,2063.79 2106.55,2050.7 2106.55,1916.25 2117.05,1905.75 2507.88,1905.75 2616.86,2014.73 2616.86,2314.48 2627.54,2325.16 2627.54,2367.08 2622.99,2371.63 2575.07,2371.63 2571.67,2368.23 2571.67,2355.12 2571.67,2342.64 2543.75,2314.72 2543.75,2306.12 2515.84,2278.21 2446.65,2278.21
5V_OB on Top Layer "TOP_LAYER_5V_OB_P1303" (solid, remove dead copper, pour order 1303): 981.4,2461.14 1019.28,2461.14 1025.94,2467.8 1025.94,2522.92 1039.4,2536.37 1478.83,2536.37 1507.28,2507.92 1507.28,2115.48 1560.02,2062.73 1560.02,1928.92 1551.94,1920.84 1278.63,1920.84 1194.85,2004.62 1001.45,2004.62 978.17,2027.9 978.17,2457.91
GND on Top Layer "TOP_LAYER_GND_P1302" (solid, remove dead copper, pour order 1302): 501.91,1999.91 809.57,1692.25 1191.89,1692.25 1218.93,1719.29 1218.93,1957.84 1187.86,1988.91 995.19,1988.91 962.83,2021.27 962.83,2223.41 947.92,2238.32 610.6,2238.32 566.91,2194.63 509.3,2194.63 501.91,2187.24
5V_SW on Top Layer "TOP_LAYER_5V_SW_P1301" (solid, remove dead copper, pour order 1301): 1026.1,2734.38 1114.35,2646.14 1448.08,2646.14 1467.24,2665.3 1467.24,2896.37 1452.28,2912.3 519.15,2912.3 507.35,2900.5 507.35,2729.5 522.88,2713.96 713.91,2713.96 724.7,2724.75 724.7,2831.38 732.66,2839.34 768.86,2839.34 802.44,2805.75 934.91,2805.75 940.19,2800.47 940.19,2743.34 948.57,2734.38
NetL2_1 on Top Layer "TOP_LAYER_NETL2_1_P1291" (solid, remove dead copper, pour order 1291): 1809.29,2475.75 1888.2,2475.75 1888.2,2666.38 1778.56,2666.38 1762.27,2650.08 1762.27,2522.77
GND on Top Layer "TOP_LAYER_GND_P1289" (solid, remove dead copper, pour order 1289): 711.17,2673.37 831.24,2673.47 835.2,2669.51 835.2,2574.39 830.91,2570.1 717.38,2570.1 712.87,2565.59 712.87,2463.83 692.53,2443.49 574.34,2443.49 554.79,2463.03 554.79,2659.03 569.13,2673.37
5V_FB on Top Layer "TOP_LAYER_5V_FB_P1288" (solid, remove dead copper, pour order 1288): 930.29,2717.43 930.29,2785.18 922.51,2792.97 825.14,2792.97 815.98,2783.8 815.98,2696.78 870.28,2642.49 870.28,2347.72 874.97,2343.29 895.76,2322.5 950.89,2322.5 964.02,2334.97 964.02,2411.15 968.25,2415.38 968.25,2679.47
GND on Top Layer "TOP_LAYER_GND_P1268" (solid, remove dead copper, pour order 1268): 1887.23,2142 1892.72,2136.51 1965.12,2136.51 1970.69,2142.08 1970.69,2288.83 1945.31,2314.21 1930.8,2328.71 1902.56,2328.71 1887.23,2313.39
3V3_PG on Top Layer "TOP_LAYER_3V3_PG_P1256" (solid, remove dead copper, pour order 1256): 1965.53,2682.13 1972.09,2688.69 2063.23,2688.69 2069.46,2682.45 2069.46,2593.39 2064.32,2588.24 1977.69,2588.24 1965.53,2600.4
GND on Top Layer "TOP_LAYER_GND_P1265" (solid, remove dead copper, pour order 1265): 2911.86,12.34 2852.59,12.34 2805.44,12.34 2798.52,19.26 2798.52,129.65 2802,133.14 2909.72,133.14 2916.79,126.07 2916.79,17.27
DMD_1V8 on Top Layer "TOP_LAYER_DMD_1V8_P1258" (solid, remove dead copper, pour order 1258): 4131.38,516.74 4178.67,469.44 4260.36,469.44 4266.16,475.24 4266.16,554.91 4258.93,562.14 4163.81,562.14 4131.38,529.71
5V on Top Layer "TOP_LAYER_5V_P1251" (solid, remove dead copper, pour order 1251): 2854.05,-132.74 2911.86,-132.74 2916.79,-127.81 2916.79,-19.01 2909.72,-11.94 2853.74,-11.94 2849.9,-15.79 2849.9,-128.59
5V on Top Layer "TOP_LAYER_5V_P1250" (solid, remove dead copper, pour order 1250): 3521.65,-171.42 3579.46,-171.42 3584.39,-166.49 3584.39,-57.69 3577.32,-50.62 3521.34,-50.62 3517.5,-54.47 3517.5,-167.27
LED_ANODE on Bottom Layer "BOTTOM_LAYER_LED_ANODE_P1343" (solid, remove dead copper, pour order 1343): 4672.72,2446.1 4454.15,2446.1 4392.71,2384.66 4392.71,2176.91 4404.18,2165.44 4494.24,2165.44 4494.24,2352.98 4515.58,2374.32 4667.55,2374.32 4678.71,2385.47 4678.71,2440.11
GND on Bottom Layer "GND" (solid, remove dead copper, pour order 1281): 4544.28,1909.19 4544.28,2055.79 4558.25,2069.76 4703.98,2069.76 4703.98,1895.22 4558.25,1895.22
VDDS33 on Bottom Layer "BOTTOM_LAYER_VDDS33_P1329" (solid, remove dead copper, pour order 1329): 650.94,215.14 657.44,221.64 657.44,278.08 649.74,285.78 534.07,285.78 526.71,278.42 526.76,221.18 532.81,215.14
1V2_PG on Bottom Layer "BOTTOM_LAYER_1V2_PG_P1339" (solid, remove dead copper, pour order 1339): 2754.1,2519.47 2532.21,2519.47 2512.4,2499.66 2512.4,2333.61 2295.18,2116.4 2295.18,1953.79 2202.07,1860.68 1726.47,1860.68 1646.84,1781.04 1646.84,1656.52 1798.12,1505.24 2735.37,1502.09 2812.39,1579.11 2812.39,2461.17
DMD_1V8 on Bottom Layer "BOTTOM_LAYER_DMD_1V8_P1340" (solid, remove dead copper, pour order 1340): 3457.7,25.7 4246.29,25.7 4264.95,44.37 4264.95,262.74 4421.85,419.63 4421.85,2012.56 4370.68,2063.72 3266.34,2063.72 3237.4,2034.78 3237.4,1034.59 3387.16,884.83 3387.16,96.24
GND on Bottom Layer "BOTTOM_LAYER_GND_P1333" (solid, pour order 1333): 1621.75,1531.09 1502.45,1531.09 1493.04,1540.5 1493.04,1643 1508.72,1658.69 1589.33,1658.69 1629.57,1618.45 1629.57,1538.91
GND on Bottom Layer "BOTTOM_LAYER_GND_P1337" (solid, remove dead copper, pour order 1337): 439.88,2614.85 635.53,2614.85 655.59,2594.79 655.59,2396.41 642.51,2383.34 437.69,2383.34 420.92,2400.11 420.92,2595.89
5V on Bottom Layer "BOTTOM_LAYER_5V_P1336" (solid, pour order 1336): 1467.81,1228.73 1459.24,1220.16 1459.24,1125.11 1467.99,1116.37 1634.66,1116.37 1643.16,1124.86 1643.16,1221.17 1635.61,1228.73
5V on Bottom Layer "BOTTOM_LAYER_5V_P1330" (solid, pour order 1330): 1525.41,1403 1408.91,1403 1401.82,1395.92 1401.82,1329.23 1409.61,1321.43 1523.12,1321.43 1531.12,1329.43 1531.12,1397.3
GND on Bottom Layer "BOTTOM_LAYER_GND_P1332" (solid, remove dead copper, pour order 1332): 1678.64,791.62 1681.97,788.29 1681.97,744.66 1677.59,740.29 1386.4,740.29 1378.39,748.3 1378.39,785.56 1384.45,791.62
VDDS33 on Bottom Layer "BOTTOM_LAYER_VDDS33_P1331" (solid, remove dead copper, pour order 1331): 1678.64,799.56 1681.97,802.89 1681.97,846.52 1677.59,850.89 1386.4,850.89 1378.39,842.88 1378.39,805.61 1384.45,799.56
VDDS33 on Bottom Layer "BOTTOM_LAYER_VDDS33_P1328" (solid, pour order 1328): 3569.05,330.38 3569.05,413.06 3562.6,419.51 3499.64,419.51 3495.91,415.77 3495.91,330.02 3502.53,323.4 3562.07,323.4
GND on Bottom Layer "BOTTOM_LAYER_GND_P1335" (solid, remove dead copper, pour order 1335): 2122.21,913.41 2122.21,1089.29 2130.37,1097.44 2205.43,1097.44 2214.09,1088.78 2214.09,915.85 2203.36,905.12 2130.5,905.12
VDDAR on Bottom Layer "BOTTOM_LAYER_VDDAR_P1334" (solid, remove dead copper, pour order 1334): 2328.67,914.49 2328.67,1087.86 2321.24,1095.3 2242.96,1095.3 2236.8,1089.4 2236.8,911.68 2243.35,905.12 2319.31,905.12
5V_SW on Bottom Layer "BOTTOM_LAYER_5V_SW_P1338" (solid, remove dead copper, pour order 1338): 1196.86,2948.45 1196.86,2691.02 1178.04,2672.2 437.32,2672.2 417.89,2691.16 417.89,2948.45
VDDS33 on POWER2 "POWER2_VDDS33_P1327" (solid, remove dead copper, pour order 1327): -211,-212.99 -211,2948.45 4739,2948.45 4739,-212.99
VBIAS on POWER2 "POWER2_VBIAS_P1326" (solid, remove dead copper, pour order 1326): 3728.31,-43.88 3728.31,247.62 3769.18,288.49 3985.45,288.49 4223.95,526.99 4223.95,808.25 4127.77,904.43 3875.66,904.43 3728.31,1053.95 3728.31,1742.95 3750.57,1765.22 4293.81,1765.22 4664.41,1765.22 4697.51,1732.11 4697.51,36.23 4651.14,-10.14 3951.47,-10.14 3897.65,-63.96 3748.38,-63.96
VDDA33_F on POWER2 "POWER2_VDDA33_F_P1323" (solid, pour order 1323): 2619.71,694.21 2830.48,694.21 2836.03,699.76 2836.03,872.07 2826.28,881.68 2497.34,881.68 2469.05,909.97 2307.36,909.97 2298.5,901.11 2298.5,714.93 2302.81,710.62 2458.41,710.62 2498.53,750.73 2602.55,750.73 2610.58,742.71 2610.58,703.34
5V on POWER2 "POWER2_5V_P1325" (solid, remove dead copper, pour order 1325): 1349.09,1096.36 1349.09,2305.31 1390.15,2346.36 1827.96,2346.36 1907.04,2267.29 1907.04,1107.35 1864.76,1065.07 1380.38,1065.07
VDDA_LDO_1V8 on POWER2 "POWER2_VDDA_LDO_1V8_P1324" (solid, remove dead copper, pour order 1324): 2867.53,596.6 2867.53,674.97 2858.49,684.01 2616.22,684.01 2610.58,678.36 2610.58,596.98 2594.84,581.24 2341.56,581.24 2329.64,569.32 2329.64,371.39 2344.38,356.64 2525.77,356.64 2874.27,356.64 2897.57,379.95 2897.57,566.55
VIN_12V on SIGNAL2 "SIGNAL2_VIN_12V_P1312" (solid, remove dead copper, pour order 1312): 1652.52,1683.54 1658.46,1689.48 2642.46,1689.48 2777.23,1554.7 3573.98,1554.7 3653.14,1633.86 3653.14,2933.32 3637.53,2948.92 -211,2948.92 -211,1567.35 -204.74,1561.08 -204.7,1554.7 -134.69,1484.69 1453.67,1484.69
VRESET on SIGNAL2 "SIGNAL2_VRESET_P1311" (solid, pour order 1311): 3746.29,262.12 3746.29,161.97 3763.24,145.02 3953.55,145.02 3966.1,132.47 3966.1,46.18 3991.77,20.52 4311.97,20.52 4464.3,172.85 4681.05,172.85 4741.93,233.73 4741.93,1369.7 4573.44,1538.19 3638.8,1537.38 3573.01,1471.58 3573.01,1189.54 3898.61,863.94 4151.41,863.94 4218.27,797.08 4218.27,601.56 3906.9,290.19 3774.36,290.19
GND on POWER1 "POWER1_GND_P1322" (solid, remove dead copper, pour order 1322): 4739.13,2948.45 -211,2948.45 -211,-210.98 4738.99,-210.98
3V3_PG on POWER1 "POWER1_3V3_PG_P1317" (solid, remove dead copper, pour order 1317): 1948.28,2310.3 1968.09,2290.5 1968.09,1852.83 1853.03,1737.77 1853.03,1512.94 1864.36,1501.47 2240.87,1501.47 2361.36,1621.95 2361.36,2528.12 2189.47,2700.01 1918.34,2700.01 1778.87,2560.54 1778.87,2385.41 1811.97,2352.32 1844.64,2352.32 1886.65,2310.3
VDDAR on POWER1 "POWER1_VDDAR_P1320" (solid, remove dead copper, pour order 1320): 2376.41,1863.51 2376.41,1613.59 2245.91,1483.08 1910.94,1483.08 1790.21,1362.36 1274.96,1362.35 1207.67,1294.74 1207.67,951.69 1262.6,896.76 1652.78,896.76 1894.17,655.37 2174.72,655.37 2208.65,689.31 2407.39,689.31 2414.56,696.48 2414.56,806.23 2437.22,828.89 2581.54,828.89 2591.28,819.16 2591.28,750.54 2578.35,737.61 2578.35,690.79 2582.7,686.43 2635.59,686.43 2642.07,679.96 2642.07,658.32 2645.02,655.37 2661.17,655.37 2911.96,655.37 2921.86,665.27 2921.86,823.18 2939.46,840.78 2991.8,840.78 3007.6,856.58 3007.6,980.06 3000.09,987.58 2926.14,987.39 2915.34,998.19 2915.34,1067.06 2895.42,1086.97 2704.82,1086.97 2690.37,1072.52 2690.37,1018.46 2679.58,1007.67 2597.3,1007.67 2570.86,1034.1 2570.86,1295.14 2603.63,1327.91 3029.31,1327.91 3071.04,1369.64 3071.04,2006.43 3005.88,2071.59 2584.49,2071.59
VDDS_LDO_1V8 on POWER1 "POWER1_VDDS_LDO_1V8_P1318" (solid, remove dead copper, pour order 1318): 3310.71,473.9 3247.6,410.78 3111.96,410.78 3102.61,420.12 2263.65,420.12 2178.94,504.84 2178.94,645.17 2212.88,679.11 2446.83,679.11 2455.34,687.63 2455.34,802.89 2471.14,818.69 2577.32,818.69 2584.07,811.95 2584.07,756.65 2578.13,750.71 2560.33,750.71 2553.58,743.96 2553.58,667.14 2559.5,661.21 2611.05,661.21 2616.23,656.02 2616.23,637.46 2623.26,630.43 2918.76,630.43 2931.66,643.33 2931.66,819.66 2943.36,831.36 2996.8,831.36 3017.8,852.35 3017.8,994.34 3009.46,1002.68 2929.43,1002.68 2925.54,1006.58 2925.54,1071.28 2899.65,1097.17 2700.6,1097.17 2678.55,1075.12 2678.55,1037.92 2674.81,1034.18 2585.21,1034.18 2578.07,1041.31 2578.07,1287.93 2607.66,1317.52 3228.79,1317.52 3310.71,1235.6
5V on POWER1 "s" (solid, remove dead copper, pour order 1321): 3305.77,301.8 3204.86,402.72 3077.37,402.72 3070.92,408.36 1324.01,408.36 1190.75,541.63 1190.75,1597.15 1324.56,1730.96 1820.65,1730.96 1875.81,1786.12 1875.81,2299.51 1838.3,2337.02 650.03,2337.02 508.56,2195.56 508.56,-81.01 638.73,-211.17 3589.47,-211.17 3604.4,-196.24 3604.4,129.84 3570.11,164.13 3443.45,164.13
VMON_5V on POWER1 "POWER1_VMON_5V_P1315" (solid, remove dead copper, pour order 1315): 1782.98,1375.56 1477.09,1375.56 1450.88,1401.78 1450.88,1693.98 1469.32,1712.42 1819.84,1712.42 1842.13,1690.13 1842.13,1525.64 1809.88,1493.39 1809.88,1402.46
VDDS33 on POWER1 "POWER1_VDDS33_P1319" (solid, remove dead copper, pour order 1319): 4396.75,858.31 4425.69,829.37 4425.69,547.81 4442.25,531.25 4582.06,531.25 4736.92,686.11 4736.92,1489.99 4679.95,1546.95 3834.39,1546.95 3572.14,1284.7 3572.14,1198.93 3896.82,874.25 3912.76,858.31
1V2_OB on POWER1 "POWER1_1V2_OB_P1316" (solid, remove dead copper, pour order 1316): 2454.16,2315.67 2612.24,2315.67 2632.19,2295.72 2632.19,2180.5 2656.2,2156.49 2870.77,2156.49 2890.87,2176.59 2890.87,2515.38 2862.8,2543.45 2450.61,2543.45 2436.72,2529.56 2436.72,2333.11
5V_FB on POWER1 "POWER1_5V_FB_P1314" (solid, remove dead copper, pour order 1314): 981.25,2363.1 981.25,2767.29 965.47,2783.07 813.03,2783.06 796.43,2766.46 796.43,2525.02 863.92,2457.53 863.92,2361.17 868.67,2356.41 974.57,2356.41
VIN_12V on SIGNAL1 "SIGNAL1_VIN_12V_P1309" (solid, remove dead copper, pour order 1309): -211,1307.38 1140.28,1307.38 1387.59,1554.7 2777.23,1554.7 3608.9,1554.7 3653.14,1598.93 3653.14,2933.32 3637.53,2948.92 -211,2948.92
3V3_OB on SIGNAL1 "SIGNAL1_3V3_OB_P1306" (solid, pour order 1306): 1716.36,2545.25 2067.46,2545.25 2099.86,2512.85 2099.86,2223.99 2076.03,2200.16 1925.74,2200.16 1908.62,2217.29 1908.62,2300.5 1890.75,2318.37 1721.23,2318.37 1704.47,2335.13 1704.47,2533.36
LED_ANODE on SIGNAL1 "SIGNAL1_LED_ANODE_P1307" (solid, pour order 1307): 3783.18,1634.09 3783.18,1578.62 3810.14,1551.66 4160.93,1551.66 4188.01,1578.74 4188.01,1988.55 4254.46,2055 4478.05,2055 4509.16,2086.11 4509.16,2407.58 4482.13,2436.19 3834.7,2436.19 3783.18,2384.66
VOFFSET on SIGNAL1 "SIGNAL1_VOFFSET_P1308" (solid, pour order 1308): 4091.08,401.3 4091.08,595.27 4217.08,721.27 4217.08,1081.68 4297.64,1160.16 4297.64,1735.05 4324.95,1762.35 4676.78,1762.35 4698.65,1740.48 4698.65,408.41 4317.23,26.98 4038.06,26.98 4012.34,52.71 4012.34,322.56
GND on GND1 "GND1_GND_P1305" (solid, remove dead copper, pour order 1305): 4739.13,2948.45 -211,2948.45 -211,-210.98 4738.99,-210.98
GND on GND2 "GND2_GND_P1313" (solid, remove dead copper, pour order 1313): 4739.13,2948.45 -211,2948.45 -211,-210.98 4738.99,-210.98

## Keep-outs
Keep-Out Layer:
  circle w1: c3988.89,-77.68 r67.81
  circle w1: c2839.59,-0.09 r27
  circle w1: c2539.59,-0.09 r27
  circle w1: c2256.28,-0.09 r27
  circle w1: c1956.28,-0.09 r27
  circle w1: c3988.89,684.13 r80
  circle w1: c3843.22,-142.64 r67.81
  circle w1: c4134.56,-142.64 r67.81
  circle w1: c4134.56,755 r67.81
  circle w1: c3843.22,755 r67.81
  lines w50: -211,-211 4739,-211 4739,2948.45 -211,2948.45 -211,-211
  text ".Layer_Name" at 366,-1069.49 h60

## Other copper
Top Layer:
  rectangle net GND: 1008.02,1727.49 1201.48,1913.54
  region net 5V_OB: 1200.16,2239.6 1006.7,2239.6 1006.7,2053.55 1200.16,2053.55
  text "1" at 2598.44,2743.77 h60
  text ".Layer_Name" at 366,-1069.49 h60
GND1:
  text "2" at 2588.44,2743.77 h60
  text "GND1" at 382.14,-1072.71 h60
SIGNAL1:
  text "3" at 2588.44,2743.77 h60
  text "SIGNAL1" at 378.64,-1074.46 h60
SIGNAL2:
  text "6" at 2588.44,2743.77 h60
  text "SIGNAL2" at 370.91,-1074.17 h60
GND2:
  text "7" at 2588.44,2743.77 h60
  text "GND2" at 379.38,-1066.76 h60
POWER1:
  text "4" at 2588.44,2743.77 h60
  text "POWER1" at 376.89,-1071.84 h60
POWER2:
  text "5" at 2588.44,2743.77 h60
  text "POWER2" at 371.65,-1073.59 h60
Bottom Layer:
  text "8" at 2588.44,2743.77 h60
  text ".Layer_Name" at 366,-1069.49 h60

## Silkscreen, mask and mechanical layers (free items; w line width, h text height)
Top Overlay:
  circle w10: c1879.46,2490.68 r1.81
  circle w10: c4380.04,1152.3 r4.87
  circle w10: c2619.42,2494.23 r3
  circle w10: c693.58,2446.43 r4.87
  circle w10: c4536.63,865.5 r3
  circle w10: c3531.53,-166.36 r4.87
  circle w15: c-96.35,2453.46 r10
  circle w10: c4439.56,1444.76 r4.87
  circle w10: c3982.04,2122.81 r4.87
  lines w6.1: 883.26,2385.63 959.52,2385.63 969.69,2395.8 ; 3786.67,977.78 3840.7,977.78 ; 4567.9,706.4 4637.9,706.4
  lines w6.5: 2004.06,738.47 2013.27,729.27 2070.31,729.27 ; 2750,1903.55 2750,1925.06 ; 3295,1903.55 3295,1925.06 ; 3924.39,1326.74 3924.39,1311.86 3932.25,1304 ; 3937.71,1528.63 3929.11,1520.03 3929.11,1473.96 3939.91,1463.15 ; 3944.99,1564.84 3963.78,1583.63 3963.78,1642.19 ; 4238.32,13.92 4238.32,-94.35 4252.17,-108.21
  text "'.PRJ_Number'.PCB_Rev" at 3681.49,2682.51 h108.27
  text "12V" at 286.81,2529.82 h30
  text "LED" at 4600.93,2471.4 h30
  text "R" at 4588.17,2278.75 h30 r90
  text "12V" at 379.08,2243.8 h30
  text "+" at 1171.78,2200.63 h70
  text "G" at 4588.17,2185.05 h30 r90
  text "S_EN" at 4170.21,2107.79 h23 r90
  text "R_EN" at 4213.37,2107.79 h23 r90
  text "B_EN" at 4256.54,2107.79 h23 r90
  text "G_EN" at 4299.71,2107.79 h23 r90
  text "B" at 4588.17,2092.67 h30 r90
  text "5V" at 1583.7,2091.55 h30
  text "3V3" at 2378.07,2010.42 h30
  text "GND" at 2587.39,1940.16 h30 r90
  text "GND" at 3136.28,1934.41 h30 r90
  text "1V2_OB" at 2957.89,1897.16 h30 r90
  text "1V2_EXT" at 2644.1,1850.85 h30
  text "1.8V_DMD_EXT" at 3090.98,1850.3 h30
  text "GND" at 2275.45,1826.96 h30 r90
  text "GND" at 1729.49,1826.09 h30 r90
  text "1.8V_DMD_OB" at 3503.43,1825.38 h30 r90
  text "5V_OB" at 1533.14,1768.43 h30 r90
  text "VOFFSET" at 4452.84,1755.46 h30
  text "VBIAS" at 4176.38,1752.8 h30
  text "1V8" at 3142.01,1747.75 h30
  text "3V3_OB" at 2078.11,1739.03 h30 r90
  text "1V2" at 2821.2,1738.15 h30
  text "5V_EXT" at 1633.96,1736.12 h30 r90
  text "3V3_EXT" at 2178.85,1709.05 h30 r90
  text "IADJ" at 3783.72,1703.31 h23 r90
  text "12V" at 636.8,1698.44 h30
  text "GND" at 869.1,1403.45 h30
  text "VRESET" at 3554.64,1295.64 h30
  text "A" at 3066.32,1118.55 h30
  text "A" at 1802.21,1000.49 h30
  text "E" at 3066.32,993.3 h30
  text "GND" at 635.36,959.96 h30
  text "A" at 3863.59,832.07 h30
  text "B" at 3902.96,832.07 h30
  text "C" at 3942.33,832.07 h30
  text "D" at 3981.7,832.07 h30
  text "E" at 4021.07,832.07 h30
  text "F" at 4060.44,832.07 h30
  text "G" at 4099.81,832.07 h30
  text "K" at 3062.16,831.38 h30
  text "F" at 1804.47,805.59 h30
  text "DMD_POWER_EN" at 3783.67,786.95 h30 r90
  text "R" at 3063.9,676.33 h30
  text "2" at 4183.3,636.69 h30
  text "BOOT SW" at 62.35,632.09 h30
  text "L" at 1800.53,599.95 h30
  text "V" at 3063.9,577.05 h30
  text "1" at 2494.59,539.41 h30 r90
  text "5" at 2627.02,534.41 h30 r90
  text "10" at 2787.48,509.42 h30 r90
  text "15" at 2945.96,509.42 h30 r90
  text "18" at 3035.63,509.42 h30 r90
  text "DMD_DISCHARGE_EN" at 4696.08,458.01 h30 r90
  text "VSYS_MON" at 2437.94,428.83 h23
  text "U" at 1801.98,365.8 h30
  text "5" at 1484.52,297.06 h30
  text "10" at 1668.55,295.61 h30
  text "1" at 1327.98,295.09 h30
  text "CHEETAH SPI" at 1008.96,204.16 h30
  text "Host Interfaces Ext" at 1839.97,196.44 h30
  text "MCU_JTAG" at 525.62,185.47 h30
  text "UART" at 1957.26,141.71 h23
  text "I2C" at 2170.7,141.71 h23
  text "15" at 4179.85,-22.74 h30
  text "GPMC NAND" at 3034.73,-106.99 h30 r90
  text "ENET RMII" at 2462.31,-125.5 h30 r90
  text "LIN" at 1968.61,-177.98 h23
  text "CAN" at 2174.55,-177.98 h23
  text ".Layer_Name" at 366,-1069.49 h60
